VERSION 5.8 ;
BUSBITCHARS "[]" ;
DIVIDERCHAR "/" ;
UNITS
    DATABASE MICRONS 1000 ;
END UNITS

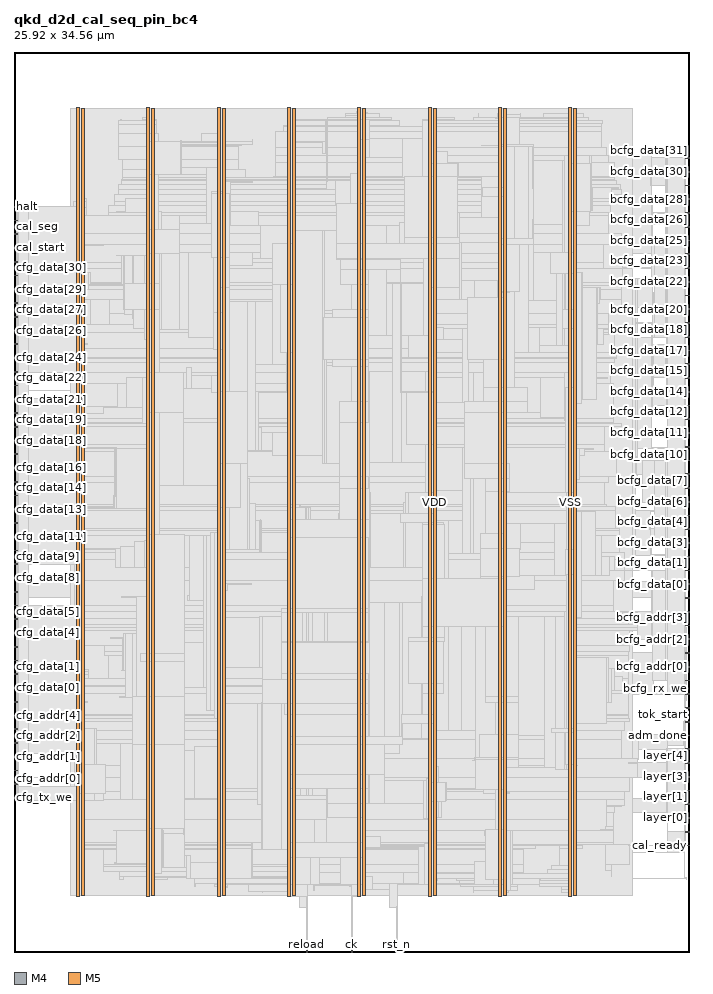
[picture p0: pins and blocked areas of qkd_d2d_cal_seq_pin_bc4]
MACRO qkd_d2d_cal_seq_pin_bc4
  FOREIGN qkd_d2d_cal_seq_pin_bc4 0 0 ;
  CLASS BLOCK ;
  SIZE 25.92 BY 34.56 ;
  PIN adm_done
    DIRECTION OUTPUT ;
    USE SIGNAL ;
    PORT
      LAYER M4 ;
        RECT  25.776 8.304 25.92 8.328 ;
    END
  END adm_done
  PIN bcfg_addr[0]
    DIRECTION INPUT ;
    USE SIGNAL ;
    PORT
      LAYER M4 ;
        RECT  25.776 10.944 25.92 10.968 ;
    END
  END bcfg_addr[0]
  PIN bcfg_addr[1]
    DIRECTION INPUT ;
    USE SIGNAL ;
    PORT
      LAYER M4 ;
        RECT  25.776 11.472 25.92 11.496 ;
    END
  END bcfg_addr[1]
  PIN bcfg_addr[2]
    DIRECTION INPUT ;
    USE SIGNAL ;
    PORT
      LAYER M4 ;
        RECT  25.776 12 25.92 12.024 ;
    END
  END bcfg_addr[2]
  PIN bcfg_addr[3]
    DIRECTION INPUT ;
    USE SIGNAL ;
    PORT
      LAYER M4 ;
        RECT  25.776 12.528 25.92 12.552 ;
    END
  END bcfg_addr[3]
  PIN bcfg_addr[4]
    DIRECTION INPUT ;
    USE SIGNAL ;
    PORT
      LAYER M4 ;
        RECT  25.776 13.056 25.92 13.08 ;
    END
  END bcfg_addr[4]
  PIN bcfg_addr[5]
    DIRECTION INPUT ;
    USE SIGNAL ;
    PORT
      LAYER M4 ;
        RECT  25.776 13.584 25.92 13.608 ;
    END
  END bcfg_addr[5]
  PIN bcfg_data[0]
    DIRECTION INPUT ;
    USE SIGNAL ;
    PORT
      LAYER M4 ;
        RECT  25.776 14.112 25.92 14.136 ;
    END
  END bcfg_data[0]
  PIN bcfg_data[10]
    DIRECTION INPUT ;
    USE SIGNAL ;
    PORT
      LAYER M4 ;
        RECT  25.776 19.392 25.92 19.416 ;
    END
  END bcfg_data[10]
  PIN bcfg_data[11]
    DIRECTION INPUT ;
    USE SIGNAL ;
    PORT
      LAYER M4 ;
        RECT  25.776 19.92 25.92 19.944 ;
    END
  END bcfg_data[11]
  PIN bcfg_data[12]
    DIRECTION INPUT ;
    USE SIGNAL ;
    PORT
      LAYER M4 ;
        RECT  25.776 20.448 25.92 20.472 ;
    END
  END bcfg_data[12]
  PIN bcfg_data[13]
    DIRECTION INPUT ;
    USE SIGNAL ;
    PORT
      LAYER M4 ;
        RECT  25.776 20.976 25.92 21 ;
    END
  END bcfg_data[13]
  PIN bcfg_data[14]
    DIRECTION INPUT ;
    USE SIGNAL ;
    PORT
      LAYER M4 ;
        RECT  25.776 21.504 25.92 21.528 ;
    END
  END bcfg_data[14]
  PIN bcfg_data[15]
    DIRECTION INPUT ;
    USE SIGNAL ;
    PORT
      LAYER M4 ;
        RECT  25.776 22.032 25.92 22.056 ;
    END
  END bcfg_data[15]
  PIN bcfg_data[16]
    DIRECTION INPUT ;
    USE SIGNAL ;
    PORT
      LAYER M4 ;
        RECT  25.776 22.56 25.92 22.584 ;
    END
  END bcfg_data[16]
  PIN bcfg_data[17]
    DIRECTION INPUT ;
    USE SIGNAL ;
    PORT
      LAYER M4 ;
        RECT  25.776 23.088 25.92 23.112 ;
    END
  END bcfg_data[17]
  PIN bcfg_data[18]
    DIRECTION INPUT ;
    USE SIGNAL ;
    PORT
      LAYER M4 ;
        RECT  25.776 23.616 25.92 23.64 ;
    END
  END bcfg_data[18]
  PIN bcfg_data[19]
    DIRECTION INPUT ;
    USE SIGNAL ;
    PORT
      LAYER M4 ;
        RECT  25.776 24.144 25.92 24.168 ;
    END
  END bcfg_data[19]
  PIN bcfg_data[1]
    DIRECTION INPUT ;
    USE SIGNAL ;
    PORT
      LAYER M4 ;
        RECT  25.776 14.64 25.92 14.664 ;
    END
  END bcfg_data[1]
  PIN bcfg_data[20]
    DIRECTION INPUT ;
    USE SIGNAL ;
    PORT
      LAYER M4 ;
        RECT  25.776 24.672 25.92 24.696 ;
    END
  END bcfg_data[20]
  PIN bcfg_data[21]
    DIRECTION INPUT ;
    USE SIGNAL ;
    PORT
      LAYER M4 ;
        RECT  25.776 25.2 25.92 25.224 ;
    END
  END bcfg_data[21]
  PIN bcfg_data[22]
    DIRECTION INPUT ;
    USE SIGNAL ;
    PORT
      LAYER M4 ;
        RECT  25.776 25.728 25.92 25.752 ;
    END
  END bcfg_data[22]
  PIN bcfg_data[23]
    DIRECTION INPUT ;
    USE SIGNAL ;
    PORT
      LAYER M4 ;
        RECT  25.776 26.256 25.92 26.28 ;
    END
  END bcfg_data[23]
  PIN bcfg_data[24]
    DIRECTION INPUT ;
    USE SIGNAL ;
    PORT
      LAYER M4 ;
        RECT  25.776 26.784 25.92 26.808 ;
    END
  END bcfg_data[24]
  PIN bcfg_data[25]
    DIRECTION INPUT ;
    USE SIGNAL ;
    PORT
      LAYER M4 ;
        RECT  25.776 27.312 25.92 27.336 ;
    END
  END bcfg_data[25]
  PIN bcfg_data[26]
    DIRECTION INPUT ;
    USE SIGNAL ;
    PORT
      LAYER M4 ;
        RECT  25.776 27.84 25.92 27.864 ;
    END
  END bcfg_data[26]
  PIN bcfg_data[27]
    DIRECTION INPUT ;
    USE SIGNAL ;
    PORT
      LAYER M4 ;
        RECT  25.776 28.368 25.92 28.392 ;
    END
  END bcfg_data[27]
  PIN bcfg_data[28]
    DIRECTION INPUT ;
    USE SIGNAL ;
    PORT
      LAYER M4 ;
        RECT  25.776 28.896 25.92 28.92 ;
    END
  END bcfg_data[28]
  PIN bcfg_data[29]
    DIRECTION INPUT ;
    USE SIGNAL ;
    PORT
      LAYER M4 ;
        RECT  25.776 29.424 25.92 29.448 ;
    END
  END bcfg_data[29]
  PIN bcfg_data[2]
    DIRECTION INPUT ;
    USE SIGNAL ;
    PORT
      LAYER M4 ;
        RECT  25.776 15.168 25.92 15.192 ;
    END
  END bcfg_data[2]
  PIN bcfg_data[30]
    DIRECTION INPUT ;
    USE SIGNAL ;
    PORT
      LAYER M4 ;
        RECT  25.776 29.952 25.92 29.976 ;
    END
  END bcfg_data[30]
  PIN bcfg_data[31]
    DIRECTION INPUT ;
    USE SIGNAL ;
    PORT
      LAYER M4 ;
        RECT  25.776 30.48 25.92 30.504 ;
    END
  END bcfg_data[31]
  PIN bcfg_data[3]
    DIRECTION INPUT ;
    USE SIGNAL ;
    PORT
      LAYER M4 ;
        RECT  25.776 15.696 25.92 15.72 ;
    END
  END bcfg_data[3]
  PIN bcfg_data[4]
    DIRECTION INPUT ;
    USE SIGNAL ;
    PORT
      LAYER M4 ;
        RECT  25.776 16.224 25.92 16.248 ;
    END
  END bcfg_data[4]
  PIN bcfg_data[5]
    DIRECTION INPUT ;
    USE SIGNAL ;
    PORT
      LAYER M4 ;
        RECT  25.776 16.752 25.92 16.776 ;
    END
  END bcfg_data[5]
  PIN bcfg_data[6]
    DIRECTION INPUT ;
    USE SIGNAL ;
    PORT
      LAYER M4 ;
        RECT  25.776 17.28 25.92 17.304 ;
    END
  END bcfg_data[6]
  PIN bcfg_data[7]
    DIRECTION INPUT ;
    USE SIGNAL ;
    PORT
      LAYER M4 ;
        RECT  25.776 17.808 25.92 17.832 ;
    END
  END bcfg_data[7]
  PIN bcfg_data[8]
    DIRECTION INPUT ;
    USE SIGNAL ;
    PORT
      LAYER M4 ;
        RECT  25.776 18.336 25.92 18.36 ;
    END
  END bcfg_data[8]
  PIN bcfg_data[9]
    DIRECTION INPUT ;
    USE SIGNAL ;
    PORT
      LAYER M4 ;
        RECT  25.776 18.864 25.92 18.888 ;
    END
  END bcfg_data[9]
  PIN bcfg_rx_we
    DIRECTION INPUT ;
    USE SIGNAL ;
    PORT
      LAYER M4 ;
        RECT  25.776 10.416 25.92 10.44 ;
    END
  END bcfg_rx_we
  PIN bcfg_tx_we
    DIRECTION INPUT ;
    USE SIGNAL ;
    PORT
      LAYER M4 ;
        RECT  25.776 9.888 25.92 9.912 ;
    END
  END bcfg_tx_we
  PIN cal_ready
    DIRECTION OUTPUT ;
    USE SIGNAL ;
    PORT
      LAYER M4 ;
        RECT  25.776 4.08 25.92 4.104 ;
    END
  END cal_ready
  PIN cal_seg
    DIRECTION OUTPUT ;
    USE SIGNAL ;
    PORT
      LAYER M4 ;
        RECT  0 27.552 0.144 27.576 ;
    END
  END cal_seg
  PIN cal_start
    DIRECTION OUTPUT ;
    USE SIGNAL ;
    PORT
      LAYER M4 ;
        RECT  0 27.024 0.144 27.048 ;
    END
  END cal_start
  PIN cfg_addr[0]
    DIRECTION OUTPUT ;
    USE SIGNAL ;
    PORT
      LAYER M4 ;
        RECT  0 6.96 0.144 6.984 ;
    END
  END cfg_addr[0]
  PIN cfg_addr[1]
    DIRECTION OUTPUT ;
    USE SIGNAL ;
    PORT
      LAYER M4 ;
        RECT  0 7.488 0.144 7.512 ;
    END
  END cfg_addr[1]
  PIN cfg_addr[2]
    DIRECTION OUTPUT ;
    USE SIGNAL ;
    PORT
      LAYER M4 ;
        RECT  0 8.016 0.144 8.04 ;
    END
  END cfg_addr[2]
  PIN cfg_addr[3]
    DIRECTION OUTPUT ;
    USE SIGNAL ;
    PORT
      LAYER M4 ;
        RECT  0 8.544 0.144 8.568 ;
    END
  END cfg_addr[3]
  PIN cfg_addr[4]
    DIRECTION OUTPUT ;
    USE SIGNAL ;
    PORT
      LAYER M4 ;
        RECT  0 9.072 0.144 9.096 ;
    END
  END cfg_addr[4]
  PIN cfg_addr[5]
    DIRECTION OUTPUT ;
    USE SIGNAL ;
    PORT
      LAYER M4 ;
        RECT  0 9.6 0.144 9.624 ;
    END
  END cfg_addr[5]
  PIN cfg_data[0]
    DIRECTION OUTPUT ;
    USE SIGNAL ;
    PORT
      LAYER M4 ;
        RECT  0 10.128 0.144 10.152 ;
    END
  END cfg_data[0]
  PIN cfg_data[10]
    DIRECTION OUTPUT ;
    USE SIGNAL ;
    PORT
      LAYER M4 ;
        RECT  0 15.408 0.144 15.432 ;
    END
  END cfg_data[10]
  PIN cfg_data[11]
    DIRECTION OUTPUT ;
    USE SIGNAL ;
    PORT
      LAYER M4 ;
        RECT  0 15.936 0.144 15.96 ;
    END
  END cfg_data[11]
  PIN cfg_data[12]
    DIRECTION OUTPUT ;
    USE SIGNAL ;
    PORT
      LAYER M4 ;
        RECT  0 16.464 0.144 16.488 ;
    END
  END cfg_data[12]
  PIN cfg_data[13]
    DIRECTION OUTPUT ;
    USE SIGNAL ;
    PORT
      LAYER M4 ;
        RECT  0 16.992 0.144 17.016 ;
    END
  END cfg_data[13]
  PIN cfg_data[14]
    DIRECTION OUTPUT ;
    USE SIGNAL ;
    PORT
      LAYER M4 ;
        RECT  0 17.52 0.144 17.544 ;
    END
  END cfg_data[14]
  PIN cfg_data[15]
    DIRECTION OUTPUT ;
    USE SIGNAL ;
    PORT
      LAYER M4 ;
        RECT  0 18.048 0.144 18.072 ;
    END
  END cfg_data[15]
  PIN cfg_data[16]
    DIRECTION OUTPUT ;
    USE SIGNAL ;
    PORT
      LAYER M4 ;
        RECT  0 18.576 0.144 18.6 ;
    END
  END cfg_data[16]
  PIN cfg_data[17]
    DIRECTION OUTPUT ;
    USE SIGNAL ;
    PORT
      LAYER M4 ;
        RECT  0 19.104 0.144 19.128 ;
    END
  END cfg_data[17]
  PIN cfg_data[18]
    DIRECTION OUTPUT ;
    USE SIGNAL ;
    PORT
      LAYER M4 ;
        RECT  0 19.632 0.144 19.656 ;
    END
  END cfg_data[18]
  PIN cfg_data[19]
    DIRECTION OUTPUT ;
    USE SIGNAL ;
    PORT
      LAYER M4 ;
        RECT  0 20.16 0.144 20.184 ;
    END
  END cfg_data[19]
  PIN cfg_data[1]
    DIRECTION OUTPUT ;
    USE SIGNAL ;
    PORT
      LAYER M4 ;
        RECT  0 10.656 0.144 10.68 ;
    END
  END cfg_data[1]
  PIN cfg_data[20]
    DIRECTION OUTPUT ;
    USE SIGNAL ;
    PORT
      LAYER M4 ;
        RECT  0 20.688 0.144 20.712 ;
    END
  END cfg_data[20]
  PIN cfg_data[21]
    DIRECTION OUTPUT ;
    USE SIGNAL ;
    PORT
      LAYER M4 ;
        RECT  0 21.216 0.144 21.24 ;
    END
  END cfg_data[21]
  PIN cfg_data[22]
    DIRECTION OUTPUT ;
    USE SIGNAL ;
    PORT
      LAYER M4 ;
        RECT  0 21.744 0.144 21.768 ;
    END
  END cfg_data[22]
  PIN cfg_data[23]
    DIRECTION OUTPUT ;
    USE SIGNAL ;
    PORT
      LAYER M4 ;
        RECT  0 22.272 0.144 22.296 ;
    END
  END cfg_data[23]
  PIN cfg_data[24]
    DIRECTION OUTPUT ;
    USE SIGNAL ;
    PORT
      LAYER M4 ;
        RECT  0 22.8 0.144 22.824 ;
    END
  END cfg_data[24]
  PIN cfg_data[25]
    DIRECTION OUTPUT ;
    USE SIGNAL ;
    PORT
      LAYER M4 ;
        RECT  0 23.328 0.144 23.352 ;
    END
  END cfg_data[25]
  PIN cfg_data[26]
    DIRECTION OUTPUT ;
    USE SIGNAL ;
    PORT
      LAYER M4 ;
        RECT  0 23.856 0.144 23.88 ;
    END
  END cfg_data[26]
  PIN cfg_data[27]
    DIRECTION OUTPUT ;
    USE SIGNAL ;
    PORT
      LAYER M4 ;
        RECT  0 24.384 0.144 24.408 ;
    END
  END cfg_data[27]
  PIN cfg_data[28]
    DIRECTION OUTPUT ;
    USE SIGNAL ;
    PORT
      LAYER M4 ;
        RECT  0 24.912 0.144 24.936 ;
    END
  END cfg_data[28]
  PIN cfg_data[29]
    DIRECTION OUTPUT ;
    USE SIGNAL ;
    PORT
      LAYER M4 ;
        RECT  0 25.44 0.144 25.464 ;
    END
  END cfg_data[29]
  PIN cfg_data[2]
    DIRECTION OUTPUT ;
    USE SIGNAL ;
    PORT
      LAYER M4 ;
        RECT  0 11.184 0.144 11.208 ;
    END
  END cfg_data[2]
  PIN cfg_data[30]
    DIRECTION OUTPUT ;
    USE SIGNAL ;
    PORT
      LAYER M4 ;
        RECT  0 25.968 0.144 25.992 ;
    END
  END cfg_data[30]
  PIN cfg_data[31]
    DIRECTION OUTPUT ;
    USE SIGNAL ;
    PORT
      LAYER M4 ;
        RECT  0 26.496 0.144 26.52 ;
    END
  END cfg_data[31]
  PIN cfg_data[3]
    DIRECTION OUTPUT ;
    USE SIGNAL ;
    PORT
      LAYER M4 ;
        RECT  0 11.712 0.144 11.736 ;
    END
  END cfg_data[3]
  PIN cfg_data[4]
    DIRECTION OUTPUT ;
    USE SIGNAL ;
    PORT
      LAYER M4 ;
        RECT  0 12.24 0.144 12.264 ;
    END
  END cfg_data[4]
  PIN cfg_data[5]
    DIRECTION OUTPUT ;
    USE SIGNAL ;
    PORT
      LAYER M4 ;
        RECT  0 12.768 0.144 12.792 ;
    END
  END cfg_data[5]
  PIN cfg_data[6]
    DIRECTION OUTPUT ;
    USE SIGNAL ;
    PORT
      LAYER M4 ;
        RECT  0 13.296 0.144 13.32 ;
    END
  END cfg_data[6]
  PIN cfg_data[7]
    DIRECTION OUTPUT ;
    USE SIGNAL ;
    PORT
      LAYER M4 ;
        RECT  0 13.824 0.144 13.848 ;
    END
  END cfg_data[7]
  PIN cfg_data[8]
    DIRECTION OUTPUT ;
    USE SIGNAL ;
    PORT
      LAYER M4 ;
        RECT  0 14.352 0.144 14.376 ;
    END
  END cfg_data[8]
  PIN cfg_data[9]
    DIRECTION OUTPUT ;
    USE SIGNAL ;
    PORT
      LAYER M4 ;
        RECT  0 14.88 0.144 14.904 ;
    END
  END cfg_data[9]
  PIN cfg_rx_we
    DIRECTION OUTPUT ;
    USE SIGNAL ;
    PORT
      LAYER M4 ;
        RECT  0 6.432 0.144 6.456 ;
    END
  END cfg_rx_we
  PIN cfg_tx_we
    DIRECTION OUTPUT ;
    USE SIGNAL ;
    PORT
      LAYER M4 ;
        RECT  0 5.904 0.144 5.928 ;
    END
  END cfg_tx_we
  PIN ck
    DIRECTION INPUT ;
    USE SIGNAL ;
    PORT
      LAYER M5 ;
        RECT  12.96 0 12.984 0.144 ;
    END
  END ck
  PIN epoch_go
    DIRECTION INPUT ;
    USE SIGNAL ;
    PORT
      LAYER M4 ;
        RECT  0 28.08 0.144 28.104 ;
    END
  END epoch_go
  PIN fault
    DIRECTION OUTPUT ;
    USE SIGNAL ;
    PORT
      LAYER M4 ;
        RECT  25.776 9.36 25.92 9.384 ;
    END
  END fault
  PIN halt
    DIRECTION INPUT ;
    USE SIGNAL ;
    PORT
      LAYER M4 ;
        RECT  0 28.608 0.144 28.632 ;
    END
  END halt
  PIN layer[0]
    DIRECTION OUTPUT ;
    USE SIGNAL ;
    PORT
      LAYER M4 ;
        RECT  25.776 5.136 25.92 5.16 ;
    END
  END layer[0]
  PIN layer[1]
    DIRECTION OUTPUT ;
    USE SIGNAL ;
    PORT
      LAYER M4 ;
        RECT  25.776 5.664 25.92 5.688 ;
    END
  END layer[1]
  PIN layer[2]
    DIRECTION OUTPUT ;
    USE SIGNAL ;
    PORT
      LAYER M4 ;
        RECT  25.776 6.192 25.92 6.216 ;
    END
  END layer[2]
  PIN layer[3]
    DIRECTION OUTPUT ;
    USE SIGNAL ;
    PORT
      LAYER M4 ;
        RECT  25.776 6.72 25.92 6.744 ;
    END
  END layer[3]
  PIN layer[4]
    DIRECTION OUTPUT ;
    USE SIGNAL ;
    PORT
      LAYER M4 ;
        RECT  25.776 7.248 25.92 7.272 ;
    END
  END layer[4]
  PIN layer[5]
    DIRECTION OUTPUT ;
    USE SIGNAL ;
    PORT
      LAYER M4 ;
        RECT  25.776 7.776 25.92 7.8 ;
    END
  END layer[5]
  PIN reload
    DIRECTION INPUT ;
    USE SIGNAL ;
    PORT
      LAYER M5 ;
        RECT  11.232 0 11.256 0.144 ;
    END
  END reload
  PIN rst_n
    DIRECTION INPUT ;
    USE SIGNAL ;
    PORT
      LAYER M5 ;
        RECT  14.688 0 14.712 0.144 ;
    END
  END rst_n
  PIN running
    DIRECTION OUTPUT ;
    USE SIGNAL ;
    PORT
      LAYER M4 ;
        RECT  25.776 4.608 25.92 4.632 ;
    END
  END running
  PIN tok_start
    DIRECTION OUTPUT ;
    USE SIGNAL ;
    PORT
      LAYER M4 ;
        RECT  25.776 8.832 25.92 8.856 ;
    END
  END tok_start
  PIN VDD
    DIRECTION INOUT ;
    USE POWER ;
    PORT
      LAYER M5 ;
        RECT  21.492 2.151 21.612 32.409 ;
        RECT  18.792 2.151 18.912 32.409 ;
        RECT  16.092 2.151 16.212 32.409 ;
        RECT  13.392 2.151 13.512 32.409 ;
        RECT  10.692 2.151 10.812 32.409 ;
        RECT  7.992 2.151 8.112 32.409 ;
        RECT  5.292 2.151 5.412 32.409 ;
        RECT  2.592 2.151 2.712 32.409 ;
    END
  END VDD
  PIN VSS
    DIRECTION INOUT ;
    USE GROUND ;
    PORT
      LAYER M5 ;
        RECT  21.3 2.137 21.42 32.423 ;
        RECT  18.6 2.137 18.72 32.423 ;
        RECT  15.9 2.137 16.02 32.423 ;
        RECT  13.2 2.137 13.32 32.423 ;
        RECT  10.5 2.137 10.62 32.423 ;
        RECT  7.8 2.137 7.92 32.423 ;
        RECT  5.1 2.137 5.22 32.423 ;
        RECT  2.4 2.137 2.52 32.423 ;
    END
  END VSS
  OBS
    LAYER RVTN ;
     RECT  2.16 2.16 23.76 2.295 ;
     RECT  2.16 2.565 23.76 2.835 ;
     RECT  2.16 3.105 23.76 3.375 ;
     RECT  2.16 3.645 23.76 3.915 ;
     RECT  2.16 4.185 23.76 4.455 ;
     RECT  2.16 4.725 23.76 4.995 ;
     RECT  2.16 5.265 23.76 5.535 ;
     RECT  2.16 5.805 23.76 6.075 ;
     RECT  2.16 6.345 23.76 6.615 ;
     RECT  2.16 6.885 23.76 7.155 ;
     RECT  2.16 7.425 23.76 7.695 ;
     RECT  2.16 7.965 23.76 8.235 ;
     RECT  2.16 8.505 23.76 8.775 ;
     RECT  2.16 9.045 23.76 9.315 ;
     RECT  2.16 9.585 23.76 9.855 ;
     RECT  2.16 10.125 23.76 10.395 ;
     RECT  2.16 10.665 23.76 10.935 ;
     RECT  2.16 11.205 23.76 11.475 ;
     RECT  2.16 11.745 23.76 12.015 ;
     RECT  2.16 12.285 23.76 12.555 ;
     RECT  2.16 12.825 23.76 13.095 ;
     RECT  2.16 13.365 23.76 13.635 ;
     RECT  2.16 13.905 23.76 14.175 ;
     RECT  2.16 14.445 23.76 14.715 ;
     RECT  2.16 14.985 23.76 15.255 ;
     RECT  2.16 15.525 23.76 15.795 ;
     RECT  2.16 16.065 23.76 16.335 ;
     RECT  2.16 16.605 23.76 16.875 ;
     RECT  2.16 17.145 23.76 17.415 ;
     RECT  2.16 17.685 23.76 17.955 ;
     RECT  2.16 18.225 23.76 18.495 ;
     RECT  2.16 18.765 23.76 19.035 ;
     RECT  2.16 19.305 23.76 19.575 ;
     RECT  2.16 19.845 23.76 20.115 ;
     RECT  2.16 20.385 23.76 20.655 ;
     RECT  2.16 20.925 23.76 21.195 ;
     RECT  2.16 21.465 23.76 21.735 ;
     RECT  2.16 22.005 23.76 22.275 ;
     RECT  2.16 22.545 23.76 22.815 ;
     RECT  2.16 23.085 23.76 23.355 ;
     RECT  2.16 23.625 23.76 23.895 ;
     RECT  2.16 24.165 23.76 24.435 ;
     RECT  2.16 24.705 23.76 24.975 ;
     RECT  2.16 25.245 23.76 25.515 ;
     RECT  2.16 25.785 23.76 26.055 ;
     RECT  2.16 26.325 23.76 26.595 ;
     RECT  2.16 26.865 23.76 27.135 ;
     RECT  2.16 27.405 23.76 27.675 ;
     RECT  2.16 27.945 23.76 28.215 ;
     RECT  2.16 28.485 23.76 28.755 ;
     RECT  2.16 29.025 23.76 29.295 ;
     RECT  2.16 29.565 23.76 29.835 ;
     RECT  2.16 30.105 23.76 30.375 ;
     RECT  2.16 30.645 23.76 30.915 ;
     RECT  2.16 31.185 23.76 31.455 ;
     RECT  2.16 31.725 23.76 31.995 ;
     RECT  2.16 32.265 23.76 32.4 ;
    LAYER RVTP ;
     RECT  2.16 2.295 23.76 2.565 ;
     RECT  2.16 2.835 23.76 3.105 ;
     RECT  2.16 3.375 23.76 3.645 ;
     RECT  2.16 3.915 23.76 4.185 ;
     RECT  2.16 4.455 23.76 4.725 ;
     RECT  2.16 4.995 23.76 5.265 ;
     RECT  2.16 5.535 23.76 5.805 ;
     RECT  2.16 6.075 23.76 6.345 ;
     RECT  2.16 6.615 23.76 6.885 ;
     RECT  2.16 7.155 23.76 7.425 ;
     RECT  2.16 7.695 23.76 7.965 ;
     RECT  2.16 8.235 23.76 8.505 ;
     RECT  2.16 8.775 23.76 9.045 ;
     RECT  2.16 9.315 23.76 9.585 ;
     RECT  2.16 9.855 23.76 10.125 ;
     RECT  2.16 10.395 23.76 10.665 ;
     RECT  2.16 10.935 23.76 11.205 ;
     RECT  2.16 11.475 23.76 11.745 ;
     RECT  2.16 12.015 23.76 12.285 ;
     RECT  2.16 12.555 23.76 12.825 ;
     RECT  2.16 13.095 23.76 13.365 ;
     RECT  2.16 13.635 23.76 13.905 ;
     RECT  2.16 14.175 23.76 14.445 ;
     RECT  2.16 14.715 23.76 14.985 ;
     RECT  2.16 15.255 23.76 15.525 ;
     RECT  2.16 15.795 23.76 16.065 ;
     RECT  2.16 16.335 23.76 16.605 ;
     RECT  2.16 16.875 23.76 17.145 ;
     RECT  2.16 17.415 23.76 17.685 ;
     RECT  2.16 17.955 23.76 18.225 ;
     RECT  2.16 18.495 23.76 18.765 ;
     RECT  2.16 19.035 23.76 19.305 ;
     RECT  2.16 19.575 23.76 19.845 ;
     RECT  2.16 20.115 23.76 20.385 ;
     RECT  2.16 20.655 23.76 20.925 ;
     RECT  2.16 21.195 23.76 21.465 ;
     RECT  2.16 21.735 23.76 22.005 ;
     RECT  2.16 22.275 23.76 22.545 ;
     RECT  2.16 22.815 23.76 23.085 ;
     RECT  2.16 23.355 23.76 23.625 ;
     RECT  2.16 23.895 23.76 24.165 ;
     RECT  2.16 24.435 23.76 24.705 ;
     RECT  2.16 24.975 23.76 25.245 ;
     RECT  2.16 25.515 23.76 25.785 ;
     RECT  2.16 26.055 23.76 26.325 ;
     RECT  2.16 26.595 23.76 26.865 ;
     RECT  2.16 27.135 23.76 27.405 ;
     RECT  2.16 27.675 23.76 27.945 ;
     RECT  2.16 28.215 23.76 28.485 ;
     RECT  2.16 28.755 23.76 29.025 ;
     RECT  2.16 29.295 23.76 29.565 ;
     RECT  2.16 29.835 23.76 30.105 ;
     RECT  2.16 30.375 23.76 30.645 ;
     RECT  2.16 30.915 23.76 31.185 ;
     RECT  2.16 31.455 23.76 31.725 ;
     RECT  2.16 31.995 23.76 32.265 ;
    LAYER M1 ;
     RECT  2.16 2.151 23.76 32.409 ;
    LAYER M2 ;
     RECT  0.139 6.696 2.16 6.714 ;
     RECT  0.535 13.608 2.16 14.238 ;
     RECT  0.535 21.546 2.16 21.564 ;
     RECT  2.16 2.151 23.76 32.409 ;
     RECT  23.76 15.228 23.855 25.848 ;
     RECT  23.855 18 23.927 25.848 ;
     RECT  23.76 7.398 23.963 8.334 ;
     RECT  23.76 12.366 23.963 12.474 ;
     RECT  23.927 18 24.179 18.018 ;
     RECT  23.855 15.228 24.431 16.938 ;
     RECT  24.431 15.228 24.467 15.786 ;
     RECT  23.927 19.35 24.467 23.616 ;
     RECT  23.76 26.838 24.467 30.636 ;
     RECT  23.76 13.608 24.503 14.238 ;
     RECT  24.467 20.7 24.503 23.616 ;
     RECT  23.927 24.75 24.503 25.848 ;
     RECT  24.467 26.838 24.503 29.016 ;
     RECT  24.467 30.618 24.503 30.636 ;
     RECT  23.76 9.9 24.539 11.502 ;
     RECT  24.503 20.7 24.539 23.346 ;
     RECT  24.503 24.75 24.539 25.308 ;
     RECT  24.431 16.92 24.611 16.938 ;
     RECT  24.539 25.29 24.611 25.308 ;
     RECT  24.467 15.228 25.043 15.246 ;
     RECT  24.539 22.05 25.043 23.346 ;
     RECT  24.503 27.918 25.043 27.936 ;
     RECT  24.503 28.998 25.043 29.016 ;
     RECT  23.76 5.346 25.079 5.904 ;
     RECT  23.963 7.776 25.079 8.334 ;
     RECT  25.043 22.05 25.079 22.068 ;
     RECT  25.043 23.328 25.079 23.346 ;
     RECT  23.76 3.816 25.115 3.834 ;
     RECT  24.539 9.9 25.115 9.918 ;
     RECT  24.467 19.35 25.115 19.368 ;
     RECT  24.539 20.7 25.115 20.718 ;
     RECT  25.079 7.938 25.727 8.334 ;
     RECT  23.76 2.808 25.735 2.826 ;
     RECT  25.727 7.938 25.763 7.956 ;
     RECT  25.735 2.808 25.835 2.862 ;
     RECT  23.963 12.456 25.835 12.474 ;
    LAYER M3 ;
     RECT  10.98 1.723 10.998 2.143 ;
     RECT  10.515 2.143 10.998 2.255 ;
     RECT  18.615 2.143 18.705 2.299 ;
     RECT  21.315 2.143 21.405 2.299 ;
     RECT  9.54 2.299 9.558 2.335 ;
     RECT  10.515 2.255 10.797 2.335 ;
     RECT  18.615 2.299 18.99 2.347 ;
     RECT  14.436 1.723 14.454 2.371 ;
     RECT  17.64 2.299 17.658 2.371 ;
     RECT  18.615 2.347 19.062 2.371 ;
     RECT  2.415 2.143 2.505 2.413 ;
     RECT  5.115 2.143 5.205 2.413 ;
     RECT  7.815 2.143 7.905 2.413 ;
     RECT  13.215 2.143 13.305 2.413 ;
     RECT  15.915 2.143 16.005 2.413 ;
     RECT  21.024 2.299 21.405 2.413 ;
     RECT  7.815 2.413 8.097 2.461 ;
     RECT  7.815 2.461 8.19 2.497 ;
     RECT  13.215 2.413 13.497 2.497 ;
     RECT  17.64 2.371 19.35 2.497 ;
     RECT  21.024 2.413 21.597 2.497 ;
     RECT  20.628 2.497 21.597 2.533 ;
     RECT  11.52 2.371 11.538 2.569 ;
     RECT  12.888 2.497 13.497 2.569 ;
     RECT  7.704 2.497 8.19 2.605 ;
     RECT  9 2.335 10.797 2.605 ;
     RECT  14.436 2.371 14.634 2.605 ;
     RECT  17.136 2.497 19.35 2.605 ;
     RECT  6.948 2.497 6.966 2.641 ;
     RECT  7.704 2.605 10.797 2.641 ;
     RECT  11.52 2.569 13.497 2.641 ;
     RECT  14.22 2.605 14.634 2.641 ;
     RECT  17.1 2.605 19.35 2.641 ;
     RECT  20.16 2.533 21.597 2.641 ;
     RECT  15.915 2.413 16.197 2.731 ;
     RECT  17.1 2.641 21.597 2.731 ;
     RECT  5.115 2.413 5.397 2.767 ;
     RECT  4.176 2.767 4.194 2.803 ;
     RECT  5.115 2.767 5.778 2.803 ;
     RECT  6.948 2.641 10.797 2.827 ;
     RECT  15.915 2.731 16.254 2.839 ;
     RECT  16.992 2.731 21.597 2.839 ;
     RECT  25.812 2.803 25.83 2.839 ;
     RECT  5.115 2.803 5.886 2.858 ;
     RECT  6.624 2.827 10.797 2.858 ;
     RECT  25.74 2.839 25.83 2.867 ;
     RECT  4.068 2.803 4.194 2.911 ;
     RECT  5.115 2.858 10.797 2.911 ;
     RECT  15.915 2.839 21.597 3.029 ;
     RECT  11.52 2.641 14.958 3.037 ;
     RECT  15.915 3.029 19.566 3.037 ;
     RECT  4.068 2.911 10.797 3.109 ;
     RECT  22.932 2.911 22.95 3.145 ;
     RECT  20.484 3.029 21.597 3.173 ;
     RECT  3.456 3.109 10.797 3.271 ;
     RECT  20.628 3.173 21.597 3.335 ;
     RECT  3.42 3.271 10.797 3.379 ;
     RECT  11.52 3.037 19.566 3.379 ;
     RECT  22.716 3.145 22.95 3.379 ;
     RECT  25.74 2.867 25.758 3.811 ;
     RECT  2.415 2.413 2.697 3.919 ;
     RECT  3.42 3.379 19.566 3.919 ;
     RECT  2.415 3.919 19.566 3.991 ;
     RECT  20.952 3.335 21.597 3.991 ;
     RECT  2.415 3.991 20.034 4.081 ;
     RECT  20.952 3.991 21.834 4.081 ;
     RECT  22.716 3.379 23.634 4.109 ;
     RECT  2.415 4.081 21.834 4.117 ;
     RECT  22.716 4.109 23.022 4.117 ;
     RECT  2.415 4.117 23.022 4.205 ;
     RECT  25.092 3.811 25.758 4.637 ;
     RECT  12.312 4.205 23.022 4.649 ;
     RECT  22.536 4.649 23.022 4.721 ;
     RECT  22.716 4.721 23.022 4.829 ;
     RECT  2.415 4.205 11.538 5.071 ;
     RECT  12.312 4.649 21.597 5.071 ;
     RECT  25.092 4.637 25.11 5.165 ;
     RECT  22.752 4.829 23.022 5.341 ;
     RECT  22.752 5.341 23.058 5.575 ;
     RECT  22.752 5.575 23.346 5.611 ;
     RECT  2.415 5.071 21.597 5.845 ;
     RECT  22.752 5.611 23.454 5.845 ;
     RECT  2.415 5.845 23.454 6.151 ;
     RECT  25.056 5.341 25.074 6.221 ;
     RECT  2.304 6.151 23.634 6.715 ;
     RECT  2.304 6.715 23.958 7.421 ;
     RECT  0.144 5.803 0.162 7.661 ;
     RECT  25.056 7.771 25.074 7.808 ;
     RECT  2.304 7.421 23.346 8.159 ;
     RECT  25.704 7.933 25.758 8.333 ;
     RECT  2.415 8.159 23.346 8.509 ;
     RECT  2.415 8.509 23.454 8.851 ;
     RECT  25.704 8.333 25.722 8.861 ;
     RECT  2.415 8.851 23.634 8.969 ;
     RECT  2.415 8.969 23.598 9.067 ;
     RECT  2.304 9.067 23.598 9.113 ;
     RECT  25.74 9.355 25.758 9.643 ;
     RECT  25.74 9.643 25.83 9.883 ;
     RECT  25.092 9.883 25.83 9.923 ;
     RECT  2.415 9.113 23.598 9.931 ;
     RECT  2.415 9.931 23.634 10.201 ;
     RECT  2.376 10.201 23.634 10.229 ;
     RECT  2.376 10.229 23.598 10.499 ;
     RECT  2.376 10.499 2.862 10.651 ;
     RECT  2.304 10.651 2.862 10.769 ;
     RECT  2.376 10.769 2.862 10.859 ;
     RECT  3.636 10.499 23.598 11.371 ;
     RECT  24.516 10.411 24.534 11.507 ;
     RECT  3.492 11.371 23.598 11.551 ;
     RECT  2.376 10.859 2.697 11.707 ;
     RECT  2.304 11.707 2.697 11.785 ;
     RECT  3.492 11.551 23.634 11.785 ;
     RECT  2.304 11.785 23.634 12.361 ;
     RECT  2.304 12.361 23.958 12.479 ;
     RECT  25.812 9.923 25.83 12.479 ;
     RECT  2.415 12.479 23.958 12.557 ;
     RECT  2.415 12.557 23.598 12.821 ;
     RECT  2.415 12.821 23.382 13.091 ;
     RECT  2.415 13.091 23.022 13.291 ;
     RECT  2.376 13.291 23.022 13.297 ;
     RECT  24.48 13.579 24.498 14.243 ;
     RECT  2.304 13.297 23.022 14.251 ;
     RECT  0.54 13.603 0.558 14.381 ;
     RECT  2.304 14.251 23.454 15.089 ;
     RECT  25.02 15.163 25.038 15.251 ;
     RECT  2.34 15.089 23.454 15.359 ;
     RECT  24.444 15.691 24.462 15.791 ;
     RECT  2.34 15.359 23.238 15.997 ;
     RECT  2.304 15.997 23.238 16.169 ;
     RECT  2.412 16.169 23.238 16.259 ;
     RECT  24.408 16.219 24.426 16.403 ;
     RECT  24.588 16.747 24.606 16.943 ;
     RECT  2.412 16.259 23.094 16.951 ;
     RECT  2.304 16.951 23.094 17.105 ;
     RECT  2.376 17.105 22.77 17.177 ;
     RECT  23.832 17.275 23.85 17.483 ;
     RECT  24.156 17.803 24.174 18.023 ;
     RECT  2.376 17.177 22.662 18.031 ;
     RECT  2.376 18.031 22.842 18.265 ;
     RECT  23.904 18.331 23.922 19.031 ;
     RECT  2.376 18.265 23.13 19.229 ;
     RECT  25.092 19.345 25.11 19.421 ;
     RECT  2.376 19.229 22.662 19.499 ;
     RECT  24.444 19.915 24.462 20.111 ;
     RECT  2.415 19.499 22.662 20.191 ;
     RECT  2.415 20.191 23.31 20.309 ;
     RECT  2.415 20.309 23.022 20.317 ;
     RECT  2.304 20.317 23.022 20.489 ;
     RECT  25.092 20.443 25.11 20.723 ;
     RECT  0.54 21.541 0.558 21.773 ;
     RECT  24.516 20.971 24.534 21.803 ;
     RECT  2.415 20.489 23.022 21.839 ;
     RECT  25.056 22.027 25.074 22.073 ;
     RECT  2.415 21.839 22.914 22.267 ;
     RECT  2.412 22.267 22.914 22.621 ;
     RECT  2.412 22.621 23.058 22.783 ;
     RECT  2.412 22.783 23.13 22.811 ;
     RECT  25.02 22.555 25.038 22.811 ;
     RECT  15.915 22.811 23.13 23.009 ;
     RECT  2.412 22.811 15.138 23.161 ;
     RECT  25.056 23.083 25.074 23.351 ;
     RECT  24.48 23.593 24.498 23.645 ;
     RECT  15.915 23.009 23.058 23.693 ;
     RECT  2.376 23.161 15.138 23.791 ;
     RECT  15.915 23.693 22.842 23.791 ;
     RECT  2.376 23.791 22.842 24.089 ;
     RECT  23.904 24.133 23.922 24.173 ;
     RECT  3.672 24.089 22.842 24.511 ;
     RECT  24.516 24.667 24.534 24.773 ;
     RECT  2.376 24.089 2.934 25.051 ;
     RECT  3.672 24.511 23.346 25.051 ;
     RECT  24.588 25.195 24.606 25.313 ;
     RECT  2.376 25.051 23.346 25.439 ;
     RECT  2.415 25.439 23.346 25.591 ;
     RECT  2.415 25.591 23.454 25.709 ;
     RECT  24.48 25.723 24.498 25.853 ;
     RECT  0.144 25.963 0.162 26.093 ;
     RECT  2.415 25.709 23.382 26.249 ;
     RECT  23.364 26.249 23.382 26.321 ;
     RECT  2.415 26.249 22.626 26.491 ;
     RECT  0.144 27.019 0.162 27.149 ;
     RECT  2.304 26.491 22.626 27.175 ;
     RECT  24.48 26.779 24.498 27.365 ;
     RECT  2.304 27.175 23.346 27.599 ;
     RECT  25.02 27.835 25.038 27.941 ;
     RECT  2.304 27.599 22.842 28.283 ;
     RECT  3.636 28.283 22.842 28.381 ;
     RECT  24.48 28.363 24.498 28.481 ;
     RECT  2.304 28.283 2.79 28.603 ;
     RECT  3.636 28.381 22.914 28.679 ;
     RECT  2.268 28.603 2.79 28.823 ;
     RECT  3.852 28.679 22.914 28.831 ;
     RECT  2.415 28.823 2.79 28.949 ;
     RECT  25.02 28.891 25.038 29.021 ;
     RECT  3.852 28.831 23.346 29.093 ;
     RECT  3.996 29.093 23.346 29.291 ;
     RECT  3.996 29.291 23.274 29.489 ;
     RECT  4.14 29.489 23.13 29.633 ;
     RECT  4.14 29.633 23.058 29.669 ;
     RECT  4.176 29.669 23.058 29.759 ;
     RECT  9.972 29.759 23.058 29.795 ;
     RECT  4.176 29.759 8.874 30.029 ;
     RECT  24.444 29.419 24.462 30.101 ;
     RECT  10.044 29.795 23.058 30.299 ;
     RECT  4.176 30.029 8.622 30.451 ;
     RECT  10.044 30.299 22.842 30.569 ;
     RECT  24.48 30.475 24.498 30.641 ;
     RECT  10.044 30.569 22.734 30.875 ;
     RECT  4.032 30.451 8.622 30.947 ;
     RECT  6.408 30.947 8.622 30.955 ;
     RECT  6.408 30.955 8.73 30.991 ;
     RECT  6.408 30.991 9.162 31.109 ;
     RECT  6.408 31.109 6.426 31.145 ;
     RECT  9.144 31.109 9.162 31.181 ;
     RECT  7.2 31.109 8.097 31.415 ;
     RECT  4.032 30.947 5.49 31.423 ;
     RECT  10.044 30.875 22.554 31.523 ;
     RECT  10.332 31.523 22.554 31.685 ;
     RECT  10.332 31.685 14.814 31.721 ;
     RECT  3.996 31.423 5.49 31.793 ;
     RECT  15.696 31.685 22.554 31.801 ;
     RECT  3.996 31.793 5.454 31.919 ;
     RECT  10.515 31.721 14.814 31.919 ;
     RECT  15.696 31.801 22.59 31.919 ;
     RECT  15.696 31.919 16.902 31.949 ;
     RECT  4.104 31.919 4.122 31.955 ;
     RECT  4.932 31.919 5.454 31.955 ;
     RECT  10.515 31.919 14.49 31.955 ;
     RECT  4.932 31.955 5.397 32.027 ;
     RECT  12.024 31.955 14.49 32.027 ;
     RECT  12.024 32.027 14.346 32.063 ;
     RECT  15.915 31.949 16.902 32.063 ;
     RECT  17.64 31.919 22.05 32.063 ;
     RECT  2.415 28.949 2.697 32.147 ;
     RECT  5.115 32.027 5.397 32.147 ;
     RECT  7.815 31.415 8.097 32.147 ;
     RECT  10.515 31.955 10.797 32.147 ;
     RECT  15.915 32.063 16.197 32.147 ;
     RECT  18.576 32.063 19.458 32.147 ;
     RECT  12.744 32.063 14.022 32.189 ;
     RECT  17.82 32.063 17.838 32.189 ;
     RECT  18.576 32.147 18.705 32.189 ;
     RECT  19.44 32.147 19.458 32.189 ;
     RECT  20.34 32.063 21.87 32.189 ;
     RECT  13.14 32.189 13.59 32.225 ;
     RECT  13.14 32.225 13.305 32.261 ;
     RECT  2.415 32.147 2.505 32.417 ;
     RECT  5.115 32.147 5.205 32.417 ;
     RECT  7.815 32.147 7.905 32.417 ;
     RECT  10.515 32.147 10.605 32.417 ;
     RECT  13.215 32.261 13.305 32.417 ;
     RECT  15.915 32.147 16.005 32.417 ;
     RECT  18.615 32.189 18.705 32.417 ;
     RECT  21.315 32.189 21.405 32.417 ;
    LAYER M4 ;
     RECT  0.108 5.904 0.133 28.632 ;
     RECT  0.133 5.808 0.173 28.632 ;
     RECT  0.173 7.632 0.569 28.632 ;
     RECT  0.173 5.808 2.408 6.36 ;
     RECT  0.569 7.632 2.408 13.32 ;
     RECT  0.569 14.88 2.408 21.24 ;
     RECT  0.569 22.272 2.408 28.632 ;
     RECT  2.408 2.148 2.512 32.412 ;
     RECT  2.512 2.418 2.704 32.142 ;
     RECT  2.704 9.6 2.837 9.624 ;
     RECT  2.704 23.328 2.837 23.352 ;
     RECT  2.704 25.44 2.873 26.088 ;
     RECT  2.873 25.632 2.945 26.088 ;
     RECT  2.704 5.808 3.089 8.568 ;
     RECT  3.089 7.152 3.161 8.568 ;
     RECT  3.089 5.808 3.449 6.168 ;
     RECT  2.704 20.688 3.449 20.952 ;
     RECT  2.704 27.12 3.449 27.144 ;
     RECT  2.704 17.04 3.836 17.064 ;
     RECT  3.836 17.04 3.877 17.544 ;
     RECT  2.704 19.344 3.877 19.368 ;
     RECT  2.704 15.456 3.913 15.48 ;
     RECT  3.877 17.04 3.923 19.368 ;
     RECT  3.841 3.408 3.949 3.432 ;
     RECT  3.805 4.656 3.949 4.68 ;
     RECT  3.449 20.928 3.985 20.952 ;
     RECT  3.449 5.856 4.093 6.168 ;
     RECT  3.161 7.152 4.093 7.992 ;
     RECT  3.913 14.784 4.093 15.48 ;
     RECT  2.945 25.632 4.129 25.656 ;
     RECT  3.949 26.736 4.129 26.76 ;
     RECT  4.129 10.8 4.165 10.824 ;
     RECT  3.697 12.048 4.165 12.072 ;
     RECT  4.165 10.8 4.201 12.072 ;
     RECT  4.129 25.632 4.213 26.76 ;
     RECT  4.213 24.672 4.237 26.76 ;
     RECT  4.057 9.792 4.273 9.816 ;
     RECT  4.201 10.8 4.273 12.216 ;
     RECT  3.949 28.416 4.273 28.44 ;
     RECT  3.985 20.928 4.309 21.816 ;
     RECT  4.093 5.856 4.549 7.992 ;
     RECT  4.273 9.792 4.549 12.216 ;
     RECT  4.237 24.48 4.561 26.76 ;
     RECT  4.561 24.336 4.597 26.76 ;
     RECT  4.093 14.784 4.633 15.576 ;
     RECT  4.549 9.552 4.705 12.216 ;
     RECT  4.129 13.632 4.705 13.656 ;
     RECT  4.309 20.928 4.921 22.056 ;
     RECT  4.633 14.784 5.029 15.768 ;
     RECT  4.597 23.952 5.029 26.76 ;
     RECT  5.029 23.52 5.101 26.76 ;
     RECT  3.949 3.408 5.108 4.68 ;
     RECT  4.549 5.856 5.108 8.472 ;
     RECT  4.705 9.552 5.108 13.656 ;
     RECT  5.029 14.784 5.108 15.816 ;
     RECT  3.923 17.04 5.108 19.32 ;
     RECT  4.921 20.304 5.108 22.056 ;
     RECT  5.101 23.52 5.108 27.144 ;
     RECT  4.273 28.416 5.108 28.92 ;
     RECT  5.108 2.148 5.212 32.412 ;
     RECT  5.212 2.418 5.404 32.142 ;
     RECT  5.404 17.904 5.555 22.776 ;
     RECT  5.404 31.392 5.555 31.416 ;
     RECT  5.404 10.08 5.573 13.416 ;
     RECT  5.404 3.024 5.645 4.776 ;
     RECT  5.573 10.08 5.681 12.936 ;
     RECT  5.404 23.904 5.681 28.44 ;
     RECT  5.645 3.264 5.717 4.776 ;
     RECT  5.717 3.264 5.753 4.68 ;
     RECT  5.404 5.808 5.789 8.472 ;
     RECT  5.789 5.808 5.933 7.752 ;
     RECT  5.681 10.176 6.041 12.936 ;
     RECT  5.933 5.856 6.149 7.752 ;
     RECT  5.681 23.904 6.371 28.296 ;
     RECT  5.404 30.24 6.373 30.264 ;
     RECT  6.373 29.856 6.419 31.128 ;
     RECT  5.404 14.784 6.505 15.96 ;
     RECT  5.555 17.904 6.515 22.248 ;
     RECT  5.753 3.264 6.563 4.536 ;
     RECT  6.563 3.264 6.613 3.72 ;
     RECT  6.515 21.648 6.613 22.248 ;
     RECT  6.371 23.904 6.685 26.856 ;
     RECT  6.649 13.488 6.757 13.704 ;
     RECT  6.505 14.784 6.757 16.008 ;
     RECT  6.613 2.832 6.761 3.72 ;
     RECT  6.613 21.648 6.797 22.44 ;
     RECT  6.149 5.904 6.937 7.752 ;
     RECT  6.041 10.176 7.261 11.88 ;
     RECT  6.757 13.488 7.261 16.008 ;
     RECT  7.261 10.176 7.405 16.008 ;
     RECT  6.371 27.984 7.405 28.296 ;
     RECT  6.419 29.856 7.405 30.12 ;
     RECT  7.405 9.264 7.549 16.008 ;
     RECT  6.797 21.648 7.585 22.152 ;
     RECT  6.685 23.616 7.669 26.856 ;
     RECT  7.549 9.264 7.693 16.104 ;
     RECT  7.693 8.976 7.801 16.104 ;
     RECT  6.761 2.832 7.808 3.432 ;
     RECT  6.937 5.904 7.808 7.896 ;
     RECT  7.801 8.976 7.808 16.296 ;
     RECT  6.515 17.904 7.808 20.328 ;
     RECT  7.585 21.504 7.808 22.152 ;
     RECT  7.669 23.136 7.808 26.856 ;
     RECT  7.405 27.984 7.808 30.12 ;
     RECT  6.419 31.104 7.808 31.128 ;
     RECT  7.808 2.148 7.912 32.412 ;
     RECT  7.912 2.418 8.104 32.142 ;
     RECT  8.104 13.872 8.201 14.136 ;
     RECT  8.104 15.456 8.291 26.856 ;
     RECT  8.104 27.888 8.317 29.592 ;
     RECT  8.291 15.456 8.963 24.984 ;
     RECT  8.963 15.456 9.029 18.168 ;
     RECT  8.201 14.112 9.101 14.136 ;
     RECT  8.104 2.832 9.109 3.96 ;
     RECT  9.109 2.832 9.155 4.2 ;
     RECT  8.291 26.352 9.173 26.856 ;
     RECT  8.317 29.568 9.173 29.592 ;
     RECT  9.029 15.456 9.281 17.208 ;
     RECT  8.963 19.248 9.281 24.984 ;
     RECT  8.104 6.288 9.349 9.528 ;
     RECT  9.281 19.248 9.389 21.528 ;
     RECT  8.317 27.888 9.389 28.44 ;
     RECT  8.104 10.944 9.421 12.84 ;
     RECT  9.281 15.456 9.445 16.584 ;
     RECT  9.173 26.64 9.457 26.856 ;
     RECT  9.389 27.888 9.457 27.912 ;
     RECT  9.445 15.36 9.491 16.584 ;
     RECT  9.155 3.936 9.493 4.2 ;
     RECT  9.349 5.664 9.493 9.528 ;
     RECT  9.389 19.248 9.497 20.136 ;
     RECT  9.493 3.936 9.5 9.528 ;
     RECT  9.5 3.936 9.541 9.576 ;
     RECT  9.421 10.944 9.541 12.888 ;
     RECT  9.497 19.248 9.925 19.944 ;
     RECT  9.281 22.56 9.925 24.984 ;
     RECT  9.541 3.936 10.261 12.888 ;
     RECT  9.389 21.504 10.465 21.528 ;
     RECT  9.925 22.56 10.465 25.656 ;
     RECT  9.155 2.832 10.508 2.856 ;
     RECT  10.261 3.936 10.508 13.176 ;
     RECT  9.491 15.36 10.508 16.104 ;
     RECT  9.925 19.056 10.508 19.944 ;
     RECT  10.465 21.504 10.508 25.656 ;
     RECT  9.457 26.64 10.508 27.912 ;
     RECT  9.241 29.616 10.508 29.64 ;
     RECT  10.508 2.148 10.612 32.412 ;
     RECT  10.612 2.148 10.804 32.142 ;
     RECT  10.804 2.148 10.969 4.2 ;
     RECT  10.804 6 11.017 17.16 ;
     RECT  11.017 6 11.233 17.064 ;
     RECT  10.969 1.728 11.267 4.2 ;
     RECT  11.233 6 11.297 13.896 ;
     RECT  11.233 15.072 11.297 17.064 ;
     RECT  11.297 15.456 11.369 17.064 ;
     RECT  11.297 6 11.459 13.416 ;
     RECT  11.267 2.592 11.729 4.2 ;
     RECT  10.804 19.056 11.833 27.72 ;
     RECT  10.804 31.104 11.833 31.128 ;
     RECT  11.833 18.768 11.909 27.72 ;
     RECT  11.459 7.92 11.939 13.416 ;
     RECT  11.909 24.336 11.939 27.72 ;
     RECT  11.833 30.672 11.969 31.128 ;
     RECT  11.909 18.768 11.981 22.776 ;
     RECT  11.729 3.648 11.989 4.2 ;
     RECT  11.459 6 11.989 6.84 ;
     RECT  10.804 29.28 11.989 29.304 ;
     RECT  11.969 30.672 12.035 31.944 ;
     RECT  12.035 31.104 12.053 31.944 ;
     RECT  11.939 8.784 12.083 13.416 ;
     RECT  11.989 29.28 12.332 29.64 ;
     RECT  11.369 15.456 12.469 16.584 ;
     RECT  11.989 3.648 12.841 6.84 ;
     RECT  12.332 28.704 12.913 29.64 ;
     RECT  11.729 2.592 13.021 2.616 ;
     RECT  12.841 3.648 13.021 6.888 ;
     RECT  12.083 8.784 13.093 11.832 ;
     RECT  13.093 8.496 13.165 11.832 ;
     RECT  12.083 12.816 13.165 13.416 ;
     RECT  12.469 15.456 13.165 16.824 ;
     RECT  13.165 15.264 13.201 16.824 ;
     RECT  13.021 2.592 13.208 6.888 ;
     RECT  13.165 8.496 13.208 13.416 ;
     RECT  13.201 14.736 13.208 16.824 ;
     RECT  11.981 18.768 13.208 22.536 ;
     RECT  11.939 24.624 13.208 27.72 ;
     RECT  12.913 28.704 13.208 29.88 ;
     RECT  12.733 32.112 13.208 32.136 ;
     RECT  13.208 2.148 13.312 32.412 ;
     RECT  13.312 2.418 13.504 32.142 ;
     RECT  13.504 5.712 13.637 22.296 ;
     RECT  13.637 5.712 13.645 17.784 ;
     RECT  13.645 14.784 13.667 17.784 ;
     RECT  13.504 30.528 13.667 31.944 ;
     RECT  13.667 14.784 13.673 17.64 ;
     RECT  13.504 2.418 13.781 2.904 ;
     RECT  13.504 4.032 14.069 4.44 ;
     RECT  13.645 5.712 14.243 13.416 ;
     RECT  13.504 23.664 14.321 27.912 ;
     RECT  13.781 2.418 14.425 2.616 ;
     RECT  13.637 18.816 14.533 22.296 ;
     RECT  14.321 23.664 14.533 25.656 ;
     RECT  14.425 1.728 14.723 2.616 ;
     RECT  14.321 26.64 14.785 27.912 ;
     RECT  14.243 7.632 14.789 13.416 ;
     RECT  14.533 18.816 14.867 25.656 ;
     RECT  14.789 7.968 14.915 13.416 ;
     RECT  13.667 30.528 14.927 31.224 ;
     RECT  13.673 14.784 14.965 16.824 ;
     RECT  14.965 14.784 15.037 17.256 ;
     RECT  14.785 26.64 15.109 28.008 ;
     RECT  14.723 2.592 15.541 2.616 ;
     RECT  14.069 4.032 15.541 4.056 ;
     RECT  14.915 8.208 15.644 13.416 ;
     RECT  14.927 29.76 15.685 31.224 ;
     RECT  14.243 5.712 15.721 6.6 ;
     RECT  14.867 23.664 15.721 25.656 ;
     RECT  15.109 26.64 15.721 28.248 ;
     RECT  15.541 2.592 15.757 4.056 ;
     RECT  15.037 14.784 15.793 17.64 ;
     RECT  14.867 18.816 15.793 22.296 ;
     RECT  15.721 5.136 15.829 6.6 ;
     RECT  15.757 2.592 15.908 4.152 ;
     RECT  15.829 5.136 15.908 6.648 ;
     RECT  15.644 8.208 15.908 13.656 ;
     RECT  15.793 14.784 15.908 17.736 ;
     RECT  15.793 18.768 15.908 22.296 ;
     RECT  15.721 23.664 15.908 28.248 ;
     RECT  15.685 29.76 15.908 31.944 ;
     RECT  15.908 2.148 16.012 32.412 ;
     RECT  16.012 2.418 16.204 32.142 ;
     RECT  16.204 4.128 16.229 4.152 ;
     RECT  16.204 5.184 16.301 7.128 ;
     RECT  16.301 5.184 16.409 6.504 ;
     RECT  16.204 23.52 16.481 23.976 ;
     RECT  16.409 5.808 16.595 6.504 ;
     RECT  16.204 29.76 16.661 30.744 ;
     RECT  16.204 8.496 16.697 16.584 ;
     RECT  16.204 31.92 16.913 31.944 ;
     RECT  16.661 29.76 17.065 30.264 ;
     RECT  16.204 25.056 17.123 28.392 ;
     RECT  16.697 8.496 17.171 14.328 ;
     RECT  17.123 25.056 17.201 27.24 ;
     RECT  16.697 15.312 17.233 16.584 ;
     RECT  16.204 17.712 17.233 19.368 ;
     RECT  16.204 21.12 17.233 22.056 ;
     RECT  16.481 23.52 17.233 23.928 ;
     RECT  17.233 21.12 17.459 23.928 ;
     RECT  17.233 15.312 17.521 19.368 ;
     RECT  17.521 15.312 17.629 19.464 ;
     RECT  17.459 21.12 17.629 22.248 ;
     RECT  16.204 2.592 17.665 2.616 ;
     RECT  17.593 7.344 17.701 7.368 ;
     RECT  17.459 23.328 17.701 23.928 ;
     RECT  17.201 25.056 17.701 25.8 ;
     RECT  17.701 7.344 17.737 7.464 ;
     RECT  17.171 8.496 17.737 13.944 ;
     RECT  17.123 28.224 17.948 28.392 ;
     RECT  17.065 29.76 17.948 29.784 ;
     RECT  16.595 6.24 18.025 6.264 ;
     RECT  17.845 4.656 18.085 4.68 ;
     RECT  18.025 6.096 18.565 6.264 ;
     RECT  17.701 23.328 18.565 25.8 ;
     RECT  17.665 2.592 18.608 3.48 ;
     RECT  18.085 4.464 18.608 4.68 ;
     RECT  18.565 6 18.608 6.264 ;
     RECT  17.737 7.344 18.608 13.944 ;
     RECT  17.629 15.312 18.608 22.248 ;
     RECT  18.565 23.28 18.608 25.8 ;
     RECT  17.201 26.832 18.608 27.24 ;
     RECT  17.948 28.224 18.608 29.784 ;
     RECT  17.953 30.96 18.608 30.984 ;
     RECT  18.493 32.016 18.608 32.04 ;
     RECT  18.608 2.148 18.712 32.412 ;
     RECT  18.712 2.352 18.904 32.142 ;
     RECT  18.904 20.736 18.929 32.04 ;
     RECT  18.904 6.096 19.037 6.12 ;
     RECT  18.904 2.352 19.073 4.68 ;
     RECT  19.073 2.592 19.145 4.68 ;
     RECT  18.929 20.736 19.217 30.984 ;
     RECT  18.904 7.104 19.379 12.888 ;
     RECT  18.904 15.456 19.468 16.44 ;
     RECT  19.217 23.04 19.757 30.984 ;
     RECT  19.757 25.008 19.955 30.984 ;
     RECT  18.904 13.92 19.973 14.472 ;
     RECT  19.145 2.592 20.189 2.808 ;
     RECT  19.757 23.04 20.189 23.976 ;
     RECT  19.217 20.736 20.221 22.056 ;
     RECT  20.189 2.784 20.225 2.808 ;
     RECT  19.379 7.104 20.365 7.176 ;
     RECT  19.379 8.304 20.365 12.888 ;
     RECT  19.973 14.448 20.761 14.472 ;
     RECT  19.468 15.744 20.761 16.44 ;
     RECT  20.365 7.104 20.797 12.888 ;
     RECT  20.189 23.28 20.833 23.976 ;
     RECT  19.955 25.008 20.833 26.856 ;
     RECT  20.833 23.28 21.049 26.856 ;
     RECT  19.955 27.936 21.049 30.408 ;
     RECT  20.221 20.544 21.121 22.056 ;
     RECT  21.049 23.28 21.121 30.408 ;
     RECT  20.797 7.008 21.157 12.888 ;
     RECT  21.121 20.544 21.157 22.248 ;
     RECT  21.157 7.008 21.229 13.08 ;
     RECT  20.761 14.448 21.229 16.44 ;
     RECT  18.904 17.664 21.229 19.368 ;
     RECT  19.145 4.128 21.308 4.68 ;
     RECT  21.229 7.008 21.308 19.368 ;
     RECT  21.157 20.4 21.308 22.248 ;
     RECT  21.121 23.28 21.308 30.6 ;
     RECT  18.929 32.016 21.308 32.04 ;
     RECT  21.308 2.148 21.412 32.412 ;
     RECT  21.412 2.418 21.604 32.142 ;
     RECT  21.604 7.152 21.629 7.176 ;
     RECT  21.604 18.144 21.701 19.32 ;
     RECT  21.604 12.864 21.773 16.92 ;
     RECT  21.773 12.864 21.809 13.08 ;
     RECT  21.604 21.072 21.809 26.088 ;
     RECT  21.809 21.216 21.845 26.088 ;
     RECT  21.701 19.056 21.917 19.32 ;
     RECT  21.604 27.888 22.097 30.6 ;
     RECT  22.097 28.464 22.169 30.6 ;
     RECT  22.169 28.464 22.204 29.352 ;
     RECT  21.917 19.296 22.241 19.32 ;
     RECT  21.773 14.448 22.313 16.92 ;
     RECT  21.845 21.216 22.385 25.512 ;
     RECT  22.169 30.576 22.385 30.6 ;
     RECT  22.385 23.328 22.421 25.512 ;
     RECT  22.421 24.912 22.493 25.512 ;
     RECT  22.493 25.056 22.529 25.512 ;
     RECT  22.313 14.448 22.565 16.008 ;
     RECT  22.421 23.328 22.637 23.928 ;
     RECT  21.604 8.784 22.745 11.304 ;
     RECT  22.385 22.032 22.781 22.056 ;
     RECT  22.745 9.6 22.817 11.304 ;
     RECT  22.565 14.448 22.853 15.192 ;
     RECT  22.637 23.904 22.853 23.928 ;
     RECT  22.817 9.6 22.961 10.872 ;
     RECT  22.204 28.944 22.961 29.352 ;
     RECT  22.961 10.032 23.069 10.872 ;
     RECT  22.853 14.64 23.069 15.192 ;
     RECT  22.961 29.328 23.213 29.352 ;
     RECT  23.069 10.032 23.357 10.584 ;
     RECT  23.605 7.248 23.929 7.272 ;
     RECT  23.353 12 23.929 12.024 ;
     RECT  23.353 13.056 23.929 13.08 ;
     RECT  23.821 17.28 24.145 17.304 ;
     RECT  23.893 18.336 24.145 18.888 ;
     RECT  24.397 16.224 24.433 16.248 ;
     RECT  23.929 12 24.469 13.08 ;
     RECT  23.069 14.64 24.469 14.664 ;
     RECT  23.893 24.144 24.469 24.168 ;
     RECT  23.353 26.256 24.469 26.28 ;
     RECT  24.433 29.424 24.469 29.976 ;
     RECT  24.469 12 24.505 14.664 ;
     RECT  24.469 23.616 24.505 24.168 ;
     RECT  24.433 15.696 24.577 16.248 ;
     RECT  24.145 17.28 24.577 18.888 ;
     RECT  24.505 23.616 24.577 24.696 ;
     RECT  24.469 25.728 24.577 27.336 ;
     RECT  24.505 10.416 25.009 14.664 ;
     RECT  24.577 15.696 25.009 18.888 ;
     RECT  24.577 23.616 25.009 27.336 ;
     RECT  24.469 28.368 25.009 28.392 ;
     RECT  24.469 29.424 25.009 30.504 ;
     RECT  23.929 6.72 25.045 7.272 ;
     RECT  24.505 20.976 25.045 21.528 ;
     RECT  25.009 22.56 25.045 22.584 ;
     RECT  25.009 23.616 25.045 30.504 ;
     RECT  25.045 5.664 25.081 7.8 ;
     RECT  25.009 10.416 25.081 18.888 ;
     RECT  24.433 19.92 25.081 19.944 ;
     RECT  25.045 20.976 25.081 30.504 ;
     RECT  23.605 4.08 25.729 4.104 ;
     RECT  25.081 5.136 25.729 7.8 ;
     RECT  25.693 8.832 25.729 8.856 ;
     RECT  25.081 9.888 25.729 30.504 ;
     RECT  25.729 4.08 25.788 30.504 ;
     RECT  25.788 9.648 25.841 9.672 ;
    LAYER M5 ;
     RECT  14.688 0.08 14.712 1.763 ;
     RECT  11.232 0.08 11.256 2.137 ;
     RECT  12.96 0.08 12.984 2.137 ;
     RECT  2.4 2.137 2.52 2.151 ;
     RECT  5.1 2.137 5.22 2.151 ;
     RECT  7.8 2.137 7.92 2.151 ;
     RECT  12.96 2.137 13.32 2.151 ;
     RECT  15.9 2.137 16.02 2.151 ;
     RECT  18.6 2.137 18.72 2.151 ;
     RECT  21.3 2.137 21.42 2.151 ;
     RECT  10.5 2.137 11.256 2.581 ;
     RECT  12.96 2.151 13.512 2.581 ;
     RECT  18.6 2.151 18.912 2.581 ;
     RECT  18.432 2.581 18.912 2.773 ;
     RECT  10.5 2.581 11.4 3.637 ;
     RECT  12.528 2.581 13.512 3.637 ;
     RECT  9.12 3.109 9.144 4.211 ;
     RECT  10.5 3.637 13.512 4.211 ;
     RECT  18.096 2.773 18.912 4.691 ;
     RECT  5.1 2.151 5.412 4.741 ;
     RECT  6.528 4.501 6.552 4.741 ;
     RECT  12 4.211 13.512 5.171 ;
     RECT  12.048 5.171 13.512 5.701 ;
     RECT  15.9 2.151 16.212 5.797 ;
     RECT  2.4 2.151 2.712 6.085 ;
     RECT  18.48 4.691 18.912 6.229 ;
     RECT  10.5 4.211 10.812 6.277 ;
     RECT  12.048 5.701 13.608 6.277 ;
     RECT  15.9 5.797 16.584 6.515 ;
     RECT  10.5 6.277 13.608 6.805 ;
     RECT  2.4 6.085 3.528 7.187 ;
     RECT  21.3 2.151 21.612 7.189 ;
     RECT  17.712 6.229 18.912 7.381 ;
     RECT  17.712 7.381 19.368 7.475 ;
     RECT  5.1 4.741 6.552 7.957 ;
     RECT  10.5 6.805 14.232 7.957 ;
     RECT  10.5 7.957 14.904 8.291 ;
     RECT  17.856 7.475 19.368 8.339 ;
     RECT  21.168 7.189 21.612 8.437 ;
     RECT  20.64 8.437 21.612 8.579 ;
     RECT  14.88 8.291 14.904 8.773 ;
     RECT  15.9 6.515 16.212 8.773 ;
     RECT  14.88 8.773 16.212 9.107 ;
     RECT  10.5 8.291 13.608 9.109 ;
     RECT  10.368 9.109 13.608 9.541 ;
     RECT  18.48 8.339 19.368 9.589 ;
     RECT  4.56 7.957 6.552 9.827 ;
     RECT  18.096 9.589 19.368 9.827 ;
     RECT  15.696 9.107 16.212 9.925 ;
     RECT  15.696 9.925 16.488 10.309 ;
     RECT  9.552 9.541 13.608 10.451 ;
     RECT  10.272 10.451 13.608 10.693 ;
     RECT  5.1 9.827 6.552 11.173 ;
     RECT  4.848 11.173 6.552 11.459 ;
     RECT  10.272 10.693 13.656 11.891 ;
     RECT  10.272 11.891 13.608 11.939 ;
     RECT  15.168 10.309 16.488 11.941 ;
     RECT  15.168 11.941 16.536 12.083 ;
     RECT  15.696 12.083 16.536 12.517 ;
     RECT  18.096 9.827 18.912 12.517 ;
     RECT  10.272 11.939 11.064 13.045 ;
     RECT  12.048 11.939 13.608 13.045 ;
     RECT  10.272 13.045 13.608 13.187 ;
     RECT  15.696 12.517 18.912 14.339 ;
     RECT  17.904 14.339 18.912 14.437 ;
     RECT  21.3 8.579 21.612 14.485 ;
     RECT  21.168 14.485 21.612 15.443 ;
     RECT  17.904 14.437 19.416 15.491 ;
     RECT  10.5 13.187 13.608 15.925 ;
     RECT  5.1 11.459 6.552 16.019 ;
     RECT  17.904 15.491 18.912 16.067 ;
     RECT  15.696 14.339 16.536 16.403 ;
     RECT  15.696 16.403 16.488 16.499 ;
     RECT  15.696 16.499 16.212 16.501 ;
     RECT  9.456 15.349 9.48 16.595 ;
     RECT  10.5 15.925 13.656 16.595 ;
     RECT  14.832 16.501 16.212 16.835 ;
     RECT  10.5 16.595 11.208 17.075 ;
     RECT  7.8 2.151 8.112 17.077 ;
     RECT  10.5 17.075 10.968 17.171 ;
     RECT  15.168 16.835 16.212 17.651 ;
     RECT  21.3 15.443 21.612 17.653 ;
     RECT  18.096 16.067 18.912 17.701 ;
     RECT  12.48 16.595 13.656 17.795 ;
     RECT  18.096 17.701 19.032 18.181 ;
     RECT  12.48 17.795 13.608 18.275 ;
     RECT  17.28 18.181 19.032 18.755 ;
     RECT  7.8 17.077 8.712 18.757 ;
     RECT  3.888 17.509 3.912 19.379 ;
     RECT  15.792 17.651 16.212 19.477 ;
     RECT  12.48 18.275 13.512 20.341 ;
     RECT  5.1 16.019 5.592 20.725 ;
     RECT  17.28 18.755 18.912 20.725 ;
     RECT  12.48 20.341 13.608 21.155 ;
     RECT  17.28 20.725 19.704 21.155 ;
     RECT  15.072 19.477 16.212 21.493 ;
     RECT  7.8 18.757 8.952 21.539 ;
     RECT  14.832 21.493 16.212 21.539 ;
     RECT  18.048 21.155 19.704 21.683 ;
     RECT  21.168 17.653 21.612 21.683 ;
     RECT  5.1 20.725 6.504 22.259 ;
     RECT  12.96 21.155 13.608 22.501 ;
     RECT  12.24 22.501 13.608 22.741 ;
     RECT  18.048 21.683 18.912 22.741 ;
     RECT  10.5 17.171 10.812 23.029 ;
     RECT  7.8 21.539 8.112 23.125 ;
     RECT  21.3 21.683 21.612 23.941 ;
     RECT  11.904 22.741 13.608 24.371 ;
     RECT  7.68 23.125 8.112 24.563 ;
     RECT  12.24 24.371 13.608 24.659 ;
     RECT  21.072 23.941 21.612 24.659 ;
     RECT  5.1 22.259 5.592 24.661 ;
     RECT  17.424 22.741 18.912 25.139 ;
     RECT  18.6 25.139 18.912 25.333 ;
     RECT  18.6 25.333 19.032 25.381 ;
     RECT  7.8 24.563 8.112 25.525 ;
     RECT  15.9 21.539 16.212 25.525 ;
     RECT  10.224 23.029 10.812 25.621 ;
     RECT  12.96 24.659 13.608 25.621 ;
     RECT  4.224 24.661 5.592 25.667 ;
     RECT  21.168 24.659 21.612 26.053 ;
     RECT  12.528 25.621 13.608 26.197 ;
     RECT  14.832 21.539 14.856 26.197 ;
     RECT  12.528 26.197 14.856 26.581 ;
     RECT  12.384 26.581 14.856 26.629 ;
     RECT  15.9 25.525 17.112 26.629 ;
     RECT  7.8 25.525 8.28 26.677 ;
     RECT  5.1 25.667 5.592 26.821 ;
     RECT  20.592 26.053 21.612 26.867 ;
     RECT  18.6 25.381 19.416 27.157 ;
     RECT  9.936 25.621 10.812 27.203 ;
     RECT  12.384 26.629 17.112 27.203 ;
     RECT  18.6 27.157 19.944 27.395 ;
     RECT  14.976 27.203 17.112 27.443 ;
     RECT  5.1 26.821 6.36 27.731 ;
     RECT  19.92 27.395 19.944 28.115 ;
     RECT  21.3 26.867 21.612 28.453 ;
     RECT  12.384 27.203 13.512 28.739 ;
     RECT  18.6 27.395 18.912 29.029 ;
     RECT  7.584 26.677 8.28 29.123 ;
     RECT  7.584 29.123 8.112 29.219 ;
     RECT  18 29.029 18.912 29.363 ;
     RECT  14.976 27.443 17.016 29.795 ;
     RECT  5.1 27.731 5.544 29.845 ;
     RECT  15.9 29.795 17.016 30.275 ;
     RECT  21.3 28.453 22.152 30.275 ;
     RECT  18.6 29.363 18.912 30.949 ;
     RECT  19.92 29.317 19.944 30.949 ;
     RECT  18.6 30.949 19.944 30.995 ;
     RECT  5.1 29.845 6.408 31.139 ;
     RECT  13.2 28.739 13.512 31.189 ;
     RECT  5.1 31.139 5.544 31.427 ;
     RECT  12 29.605 12.024 31.955 ;
     RECT  13.2 31.189 13.656 31.955 ;
     RECT  18.6 30.995 19.416 32.051 ;
     RECT  2.4 7.187 2.712 32.409 ;
     RECT  5.1 31.427 5.412 32.409 ;
     RECT  7.8 29.219 8.112 32.409 ;
     RECT  10.5 27.203 10.812 32.409 ;
     RECT  13.2 31.955 13.512 32.409 ;
     RECT  15.9 30.275 16.212 32.409 ;
     RECT  18.6 32.051 18.912 32.409 ;
     RECT  21.3 30.275 21.612 32.409 ;
     RECT  2.4 32.409 2.52 32.423 ;
     RECT  5.1 32.409 5.22 32.423 ;
     RECT  7.8 32.409 7.92 32.423 ;
     RECT  10.5 32.409 10.62 32.423 ;
     RECT  13.2 32.409 13.32 32.423 ;
     RECT  15.9 32.409 16.02 32.423 ;
     RECT  18.6 32.409 18.72 32.423 ;
     RECT  21.3 32.409 21.42 32.423 ;
  END
END qkd_d2d_cal_seq_pin_bc4
END LIBRARY
